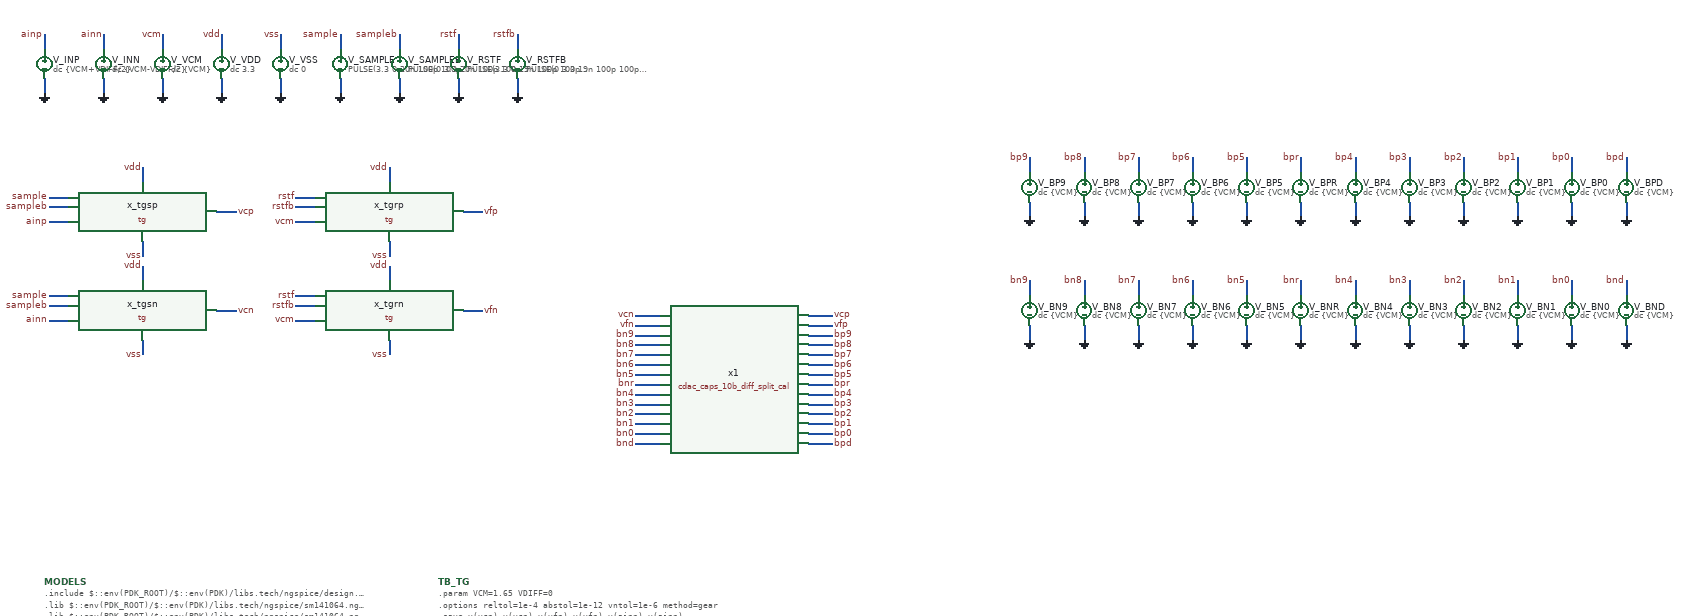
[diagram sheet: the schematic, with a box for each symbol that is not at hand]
v {xschem version=3.4.8RC file_version=1.3}
G {}
K {}
V {}
S {}
F {}
E {}
N 1650 -840 1700 -840 {
lab=vcp}
N 1650 -820 1700 -820 {
lab=vfp}
N 1650 -800 1700 -800 {
lab=bp9}
N 1650 -780 1700 -780 {
lab=bp8}
N 1650 -760 1700 -760 {
lab=bp7}
N 1650 -740 1700 -740 {
lab=bp6}
N 1650 -720 1700 -720 {
lab=bp5}
N 1650 -700 1700 -700 {
lab=bpr}
N 1650 -680 1700 -680 {
lab=bp4}
N 1650 -660 1700 -660 {
lab=bp3}
N 1650 -640 1700 -640 {
lab=bp2}
N 1650 -620 1700 -620 {
lab=bp1}
N 1650 -600 1700 -600 {
lab=bp0}
N 1650 -580 1700 -580 {
lab=bpd}
N 1300 -840 1350 -840 {
lab=vcn}
N 1300 -820 1350 -820 {
lab=vfn}
N 1300 -800 1350 -800 {
lab=bn9}
N 1300 -780 1350 -780 {
lab=bn8}
N 1300 -760 1350 -760 {
lab=bn7}
N 1300 -740 1350 -740 {
lab=bn6}
N 1300 -720 1350 -720 {
lab=bn5}
N 1300 -700 1350 -700 {
lab=bnr}
N 1300 -680 1350 -680 {
lab=bn4}
N 1300 -660 1350 -660 {
lab=bn3}
N 1300 -640 1350 -640 {
lab=bn2}
N 1300 -620 1350 -620 {
lab=bn1}
N 1300 -600 1350 -600 {
lab=bn0}
N 1300 -580 1350 -580 {
lab=bnd}
N 2100 -1160 2100 -1130 {
lab=bp9}
N 2100 -1070 2100 -1040 {
lab=GND}
N 2100 -910 2100 -880 {
lab=bn9}
N 2100 -820 2100 -790 {
lab=GND}
N 2210 -1160 2210 -1130 {
lab=bp8}
N 2210 -1070 2210 -1040 {
lab=GND}
N 2210 -910 2210 -880 {
lab=bn8}
N 2210 -820 2210 -790 {
lab=GND}
N 2320 -1160 2320 -1130 {
lab=bp7}
N 2320 -1070 2320 -1040 {
lab=GND}
N 2320 -910 2320 -880 {
lab=bn7}
N 2320 -820 2320 -790 {
lab=GND}
N 2430 -1160 2430 -1130 {
lab=bp6}
N 2430 -1070 2430 -1040 {
lab=GND}
N 2430 -910 2430 -880 {
lab=bn6}
N 2430 -820 2430 -790 {
lab=GND}
N 2540 -1160 2540 -1130 {
lab=bp5}
N 2540 -1070 2540 -1040 {
lab=GND}
N 2540 -910 2540 -880 {
lab=bn5}
N 2540 -820 2540 -790 {
lab=GND}
N 2650 -1160 2650 -1130 {
lab=bpr}
N 2650 -1070 2650 -1040 {
lab=GND}
N 2650 -910 2650 -880 {
lab=bnr}
N 2650 -820 2650 -790 {
lab=GND}
N 2760 -1160 2760 -1130 {
lab=bp4}
N 2760 -1070 2760 -1040 {
lab=GND}
N 2760 -910 2760 -880 {
lab=bn4}
N 2760 -820 2760 -790 {
lab=GND}
N 2870 -1160 2870 -1130 {
lab=bp3}
N 2870 -1070 2870 -1040 {
lab=GND}
N 2870 -910 2870 -880 {
lab=bn3}
N 2870 -820 2870 -790 {
lab=GND}
N 2980 -1160 2980 -1130 {
lab=bp2}
N 2980 -1070 2980 -1040 {
lab=GND}
N 2980 -910 2980 -880 {
lab=bn2}
N 2980 -820 2980 -790 {
lab=GND}
N 3090 -1160 3090 -1130 {
lab=bp1}
N 3090 -1070 3090 -1040 {
lab=GND}
N 3090 -910 3090 -880 {
lab=bn1}
N 3090 -820 3090 -790 {
lab=GND}
N 3200 -1160 3200 -1130 {
lab=bp0}
N 3200 -1070 3200 -1040 {
lab=GND}
N 3200 -910 3200 -880 {
lab=bn0}
N 3200 -820 3200 -790 {
lab=GND}
N 3310 -1160 3310 -1130 {
lab=bpd}
N 3310 -1070 3310 -1040 {
lab=GND}
N 3310 -910 3310 -880 {
lab=bnd}
N 3310 -820 3310 -790 {
lab=GND}
N 100 -1410 100 -1380 {
lab=ainp}
N 100 -1320 100 -1290 {
lab=GND}
N 220 -1410 220 -1380 {
lab=ainn}
N 220 -1320 220 -1290 {
lab=GND}
N 340 -1410 340 -1380 {
lab=vcm}
N 340 -1320 340 -1290 {
lab=GND}
N 460 -1410 460 -1380 {
lab=vdd}
N 460 -1320 460 -1290 {
lab=GND}
N 580 -1410 580 -1380 {
lab=vss}
N 580 -1320 580 -1290 {
lab=GND}
N 700 -1410 700 -1380 {
lab=sample}
N 700 -1320 700 -1290 {
lab=GND}
N 820 -1410 820 -1380 {
lab=sampleb}
N 820 -1320 820 -1290 {
lab=GND}
N 940 -1410 940 -1380 {
lab=rstf}
N 940 -1320 940 -1290 {
lab=GND}
N 1060 -1410 1060 -1380 {
lab=rstfb}
N 1060 -1320 1060 -1290 {
lab=GND}
N 110 -1080 150 -1080 {
lab=sample}
N 110 -1060 150 -1060 {
lab=sampleb}
N 110 -1030 150 -1030 {
lab=ainp}
N 450 -1050 490 -1050 {
lab=vcp}
N 300 -1140 300 -1110 {
lab=vdd}
N 300 -990 300 -960 {
lab=vss}
N 110 -880 150 -880 {
lab=sample}
N 110 -860 150 -860 {
lab=sampleb}
N 110 -830 150 -830 {
lab=ainn}
N 450 -850 490 -850 {
lab=vcn}
N 300 -940 300 -910 {
lab=vdd}
N 300 -790 300 -760 {
lab=vss}
N 610 -1080 650 -1080 {
lab=rstf}
N 610 -1060 650 -1060 {
lab=rstfb}
N 610 -1030 650 -1030 {
lab=vcm}
N 950 -1050 990 -1050 {
lab=vfp}
N 800 -1140 800 -1110 {
lab=vdd}
N 800 -990 800 -960 {
lab=vss}
N 610 -880 650 -880 {
lab=rstf}
N 610 -860 650 -860 {
lab=rstfb}
N 610 -830 650 -830 {
lab=vcm}
N 950 -850 990 -850 {
lab=vfn}
N 800 -940 800 -910 {
lab=vdd}
N 800 -790 800 -760 {
lab=vss}
C {cdac_caps_10b_diff_split_cal.sym} 1500 -700 0 0 {name=x1}
C {lab_pin.sym} 1700 -840 2 0 {name=l_vcp sig_type=std_logic lab=vcp}
C {lab_pin.sym} 1700 -820 2 0 {name=l_vfp sig_type=std_logic lab=vfp}
C {lab_pin.sym} 1700 -800 2 0 {name=l_bp9 sig_type=std_logic lab=bp9}
C {lab_pin.sym} 1700 -780 2 0 {name=l_bp8 sig_type=std_logic lab=bp8}
C {lab_pin.sym} 1700 -760 2 0 {name=l_bp7 sig_type=std_logic lab=bp7}
C {lab_pin.sym} 1700 -740 2 0 {name=l_bp6 sig_type=std_logic lab=bp6}
C {lab_pin.sym} 1700 -720 2 0 {name=l_bp5 sig_type=std_logic lab=bp5}
C {lab_pin.sym} 1700 -700 2 0 {name=l_bpr sig_type=std_logic lab=bpr}
C {lab_pin.sym} 1700 -680 2 0 {name=l_bp4 sig_type=std_logic lab=bp4}
C {lab_pin.sym} 1700 -660 2 0 {name=l_bp3 sig_type=std_logic lab=bp3}
C {lab_pin.sym} 1700 -640 2 0 {name=l_bp2 sig_type=std_logic lab=bp2}
C {lab_pin.sym} 1700 -620 2 0 {name=l_bp1 sig_type=std_logic lab=bp1}
C {lab_pin.sym} 1700 -600 2 0 {name=l_bp0 sig_type=std_logic lab=bp0}
C {lab_pin.sym} 1700 -580 2 0 {name=l_bpd sig_type=std_logic lab=bpd}
C {lab_pin.sym} 1300 -840 0 0 {name=l_vcn sig_type=std_logic lab=vcn}
C {lab_pin.sym} 1300 -820 0 0 {name=l_vfn sig_type=std_logic lab=vfn}
C {lab_pin.sym} 1300 -800 0 0 {name=l_bn9 sig_type=std_logic lab=bn9}
C {lab_pin.sym} 1300 -780 0 0 {name=l_bn8 sig_type=std_logic lab=bn8}
C {lab_pin.sym} 1300 -760 0 0 {name=l_bn7 sig_type=std_logic lab=bn7}
C {lab_pin.sym} 1300 -740 0 0 {name=l_bn6 sig_type=std_logic lab=bn6}
C {lab_pin.sym} 1300 -720 0 0 {name=l_bn5 sig_type=std_logic lab=bn5}
C {lab_pin.sym} 1300 -700 0 0 {name=l_bnr sig_type=std_logic lab=bnr}
C {lab_pin.sym} 1300 -680 0 0 {name=l_bn4 sig_type=std_logic lab=bn4}
C {lab_pin.sym} 1300 -660 0 0 {name=l_bn3 sig_type=std_logic lab=bn3}
C {lab_pin.sym} 1300 -640 0 0 {name=l_bn2 sig_type=std_logic lab=bn2}
C {lab_pin.sym} 1300 -620 0 0 {name=l_bn1 sig_type=std_logic lab=bn1}
C {lab_pin.sym} 1300 -600 0 0 {name=l_bn0 sig_type=std_logic lab=bn0}
C {lab_pin.sym} 1300 -580 0 0 {name=l_bnd sig_type=std_logic lab=bnd}
C {vsource.sym} 2100 -1100 0 0 {name=V_BP9 value="dc \{VCM\}" savecurrent=false}
C {lab_pin.sym} 2100 -1160 0 0 {name=lV_BP9 sig_type=std_logic lab=bp9}
C {gnd.sym} 2100 -1040 0 0 {name=gV_BP9 lab=GND}
C {vsource.sym} 2100 -850 0 0 {name=V_BN9 value="dc \{VCM\}" savecurrent=false}
C {lab_pin.sym} 2100 -910 0 0 {name=lV_BN9 sig_type=std_logic lab=bn9}
C {gnd.sym} 2100 -790 0 0 {name=gV_BN9 lab=GND}
C {vsource.sym} 2210 -1100 0 0 {name=V_BP8 value="dc \{VCM\}" savecurrent=false}
C {lab_pin.sym} 2210 -1160 0 0 {name=lV_BP8 sig_type=std_logic lab=bp8}
C {gnd.sym} 2210 -1040 0 0 {name=gV_BP8 lab=GND}
C {vsource.sym} 2210 -850 0 0 {name=V_BN8 value="dc \{VCM\}" savecurrent=false}
C {lab_pin.sym} 2210 -910 0 0 {name=lV_BN8 sig_type=std_logic lab=bn8}
C {gnd.sym} 2210 -790 0 0 {name=gV_BN8 lab=GND}
C {vsource.sym} 2320 -1100 0 0 {name=V_BP7 value="dc \{VCM\}" savecurrent=false}
C {lab_pin.sym} 2320 -1160 0 0 {name=lV_BP7 sig_type=std_logic lab=bp7}
C {gnd.sym} 2320 -1040 0 0 {name=gV_BP7 lab=GND}
C {vsource.sym} 2320 -850 0 0 {name=V_BN7 value="dc \{VCM\}" savecurrent=false}
C {lab_pin.sym} 2320 -910 0 0 {name=lV_BN7 sig_type=std_logic lab=bn7}
C {gnd.sym} 2320 -790 0 0 {name=gV_BN7 lab=GND}
C {vsource.sym} 2430 -1100 0 0 {name=V_BP6 value="dc \{VCM\}" savecurrent=false}
C {lab_pin.sym} 2430 -1160 0 0 {name=lV_BP6 sig_type=std_logic lab=bp6}
C {gnd.sym} 2430 -1040 0 0 {name=gV_BP6 lab=GND}
C {vsource.sym} 2430 -850 0 0 {name=V_BN6 value="dc \{VCM\}" savecurrent=false}
C {lab_pin.sym} 2430 -910 0 0 {name=lV_BN6 sig_type=std_logic lab=bn6}
C {gnd.sym} 2430 -790 0 0 {name=gV_BN6 lab=GND}
C {vsource.sym} 2540 -1100 0 0 {name=V_BP5 value="dc \{VCM\}" savecurrent=false}
C {lab_pin.sym} 2540 -1160 0 0 {name=lV_BP5 sig_type=std_logic lab=bp5}
C {gnd.sym} 2540 -1040 0 0 {name=gV_BP5 lab=GND}
C {vsource.sym} 2540 -850 0 0 {name=V_BN5 value="dc \{VCM\}" savecurrent=false}
C {lab_pin.sym} 2540 -910 0 0 {name=lV_BN5 sig_type=std_logic lab=bn5}
C {gnd.sym} 2540 -790 0 0 {name=gV_BN5 lab=GND}
C {vsource.sym} 2650 -1100 0 0 {name=V_BPR value="dc \{VCM\}" savecurrent=false}
C {lab_pin.sym} 2650 -1160 0 0 {name=lV_BPR sig_type=std_logic lab=bpr}
C {gnd.sym} 2650 -1040 0 0 {name=gV_BPR lab=GND}
C {vsource.sym} 2650 -850 0 0 {name=V_BNR value="dc \{VCM\}" savecurrent=false}
C {lab_pin.sym} 2650 -910 0 0 {name=lV_BNR sig_type=std_logic lab=bnr}
C {gnd.sym} 2650 -790 0 0 {name=gV_BNR lab=GND}
C {vsource.sym} 2760 -1100 0 0 {name=V_BP4 value="dc \{VCM\}" savecurrent=false}
C {lab_pin.sym} 2760 -1160 0 0 {name=lV_BP4 sig_type=std_logic lab=bp4}
C {gnd.sym} 2760 -1040 0 0 {name=gV_BP4 lab=GND}
C {vsource.sym} 2760 -850 0 0 {name=V_BN4 value="dc \{VCM\}" savecurrent=false}
C {lab_pin.sym} 2760 -910 0 0 {name=lV_BN4 sig_type=std_logic lab=bn4}
C {gnd.sym} 2760 -790 0 0 {name=gV_BN4 lab=GND}
C {vsource.sym} 2870 -1100 0 0 {name=V_BP3 value="dc \{VCM\}" savecurrent=false}
C {lab_pin.sym} 2870 -1160 0 0 {name=lV_BP3 sig_type=std_logic lab=bp3}
C {gnd.sym} 2870 -1040 0 0 {name=gV_BP3 lab=GND}
C {vsource.sym} 2870 -850 0 0 {name=V_BN3 value="dc \{VCM\}" savecurrent=false}
C {lab_pin.sym} 2870 -910 0 0 {name=lV_BN3 sig_type=std_logic lab=bn3}
C {gnd.sym} 2870 -790 0 0 {name=gV_BN3 lab=GND}
C {vsource.sym} 2980 -1100 0 0 {name=V_BP2 value="dc \{VCM\}" savecurrent=false}
C {lab_pin.sym} 2980 -1160 0 0 {name=lV_BP2 sig_type=std_logic lab=bp2}
C {gnd.sym} 2980 -1040 0 0 {name=gV_BP2 lab=GND}
C {vsource.sym} 2980 -850 0 0 {name=V_BN2 value="dc \{VCM\}" savecurrent=false}
C {lab_pin.sym} 2980 -910 0 0 {name=lV_BN2 sig_type=std_logic lab=bn2}
C {gnd.sym} 2980 -790 0 0 {name=gV_BN2 lab=GND}
C {vsource.sym} 3090 -1100 0 0 {name=V_BP1 value="dc \{VCM\}" savecurrent=false}
C {lab_pin.sym} 3090 -1160 0 0 {name=lV_BP1 sig_type=std_logic lab=bp1}
C {gnd.sym} 3090 -1040 0 0 {name=gV_BP1 lab=GND}
C {vsource.sym} 3090 -850 0 0 {name=V_BN1 value="dc \{VCM\}" savecurrent=false}
C {lab_pin.sym} 3090 -910 0 0 {name=lV_BN1 sig_type=std_logic lab=bn1}
C {gnd.sym} 3090 -790 0 0 {name=gV_BN1 lab=GND}
C {vsource.sym} 3200 -1100 0 0 {name=V_BP0 value="dc \{VCM\}" savecurrent=false}
C {lab_pin.sym} 3200 -1160 0 0 {name=lV_BP0 sig_type=std_logic lab=bp0}
C {gnd.sym} 3200 -1040 0 0 {name=gV_BP0 lab=GND}
C {vsource.sym} 3200 -850 0 0 {name=V_BN0 value="dc \{VCM\}" savecurrent=false}
C {lab_pin.sym} 3200 -910 0 0 {name=lV_BN0 sig_type=std_logic lab=bn0}
C {gnd.sym} 3200 -790 0 0 {name=gV_BN0 lab=GND}
C {vsource.sym} 3310 -1100 0 0 {name=V_BPD value="dc \{VCM\}" savecurrent=false}
C {lab_pin.sym} 3310 -1160 0 0 {name=lV_BPD sig_type=std_logic lab=bpd}
C {gnd.sym} 3310 -1040 0 0 {name=gV_BPD lab=GND}
C {vsource.sym} 3310 -850 0 0 {name=V_BND value="dc \{VCM\}" savecurrent=false}
C {lab_pin.sym} 3310 -910 0 0 {name=lV_BND sig_type=std_logic lab=bnd}
C {gnd.sym} 3310 -790 0 0 {name=gV_BND lab=GND}
C {vsource.sym} 100 -1350 0 0 {name=V_INP value="dc \{VCM+VDIFF/2\}" savecurrent=false}
C {lab_pin.sym} 100 -1410 0 0 {name=lV_INP sig_type=std_logic lab=ainp}
C {gnd.sym} 100 -1290 0 0 {name=gV_INP lab=GND}
C {vsource.sym} 220 -1350 0 0 {name=V_INN value="dc \{VCM-VDIFF/2\}" savecurrent=false}
C {lab_pin.sym} 220 -1410 0 0 {name=lV_INN sig_type=std_logic lab=ainn}
C {gnd.sym} 220 -1290 0 0 {name=gV_INN lab=GND}
C {vsource.sym} 340 -1350 0 0 {name=V_VCM value="dc \{VCM\}" savecurrent=false}
C {lab_pin.sym} 340 -1410 0 0 {name=lV_VCM sig_type=std_logic lab=vcm}
C {gnd.sym} 340 -1290 0 0 {name=gV_VCM lab=GND}
C {vsource.sym} 460 -1350 0 0 {name=V_VDD value="dc 3.3" savecurrent=false}
C {lab_pin.sym} 460 -1410 0 0 {name=lV_VDD sig_type=std_logic lab=vdd}
C {gnd.sym} 460 -1290 0 0 {name=gV_VDD lab=GND}
C {vsource.sym} 580 -1350 0 0 {name=V_VSS value="dc 0" savecurrent=false}
C {lab_pin.sym} 580 -1410 0 0 {name=lV_VSS sig_type=std_logic lab=vss}
C {gnd.sym} 580 -1290 0 0 {name=gV_VSS lab=GND}
C {vsource.sym} 700 -1350 0 0 {name=V_SAMPLE value="PULSE(3.3 0 20n 100p 100p 1 2)" savecurrent=false}
C {lab_pin.sym} 700 -1410 0 0 {name=lV_SAMPLE sig_type=std_logic lab=sample}
C {gnd.sym} 700 -1290 0 0 {name=gV_SAMPLE lab=GND}
C {vsource.sym} 820 -1350 0 0 {name=V_SAMPLEB value="PULSE(0 3.3 20n 100p 100p 1 2)" savecurrent=false}
C {lab_pin.sym} 820 -1410 0 0 {name=lV_SAMPLEB sig_type=std_logic lab=sampleb}
C {gnd.sym} 820 -1290 0 0 {name=gV_SAMPLEB lab=GND}
C {vsource.sym} 940 -1350 0 0 {name=V_RSTF value="PULSE(3.3 0 19n 100p 100p 1 2)" savecurrent=false}
C {lab_pin.sym} 940 -1410 0 0 {name=lV_RSTF sig_type=std_logic lab=rstf}
C {gnd.sym} 940 -1290 0 0 {name=gV_RSTF lab=GND}
C {vsource.sym} 1060 -1350 0 0 {name=V_RSTFB value="PULSE(0 3.3 19n 100p 100p 1 2)" savecurrent=false}
C {lab_pin.sym} 1060 -1410 0 0 {name=lV_RSTFB sig_type=std_logic lab=rstfb}
C {gnd.sym} 1060 -1290 0 0 {name=gV_RSTFB lab=GND}
C {tg.sym} 300 -1050 0 0 {name=x_tgsp}
C {lab_pin.sym} 110 -1080 0 0 {name=lx_tgspsample sig_type=std_logic lab=sample}
C {lab_pin.sym} 110 -1060 0 0 {name=lx_tgspsampleb sig_type=std_logic lab=sampleb}
C {lab_pin.sym} 110 -1030 0 0 {name=lx_tgspainp sig_type=std_logic lab=ainp}
C {lab_pin.sym} 490 -1050 2 0 {name=lx_tgspvcp sig_type=std_logic lab=vcp}
C {lab_pin.sym} 300 -1140 0 0 {name=lx_tgspvdd sig_type=std_logic lab=vdd}
C {lab_pin.sym} 300 -960 0 0 {name=lx_tgspvss sig_type=std_logic lab=vss}
C {tg.sym} 300 -850 0 0 {name=x_tgsn}
C {lab_pin.sym} 110 -880 0 0 {name=lx_tgsnsample sig_type=std_logic lab=sample}
C {lab_pin.sym} 110 -860 0 0 {name=lx_tgsnsampleb sig_type=std_logic lab=sampleb}
C {lab_pin.sym} 110 -830 0 0 {name=lx_tgsnainn sig_type=std_logic lab=ainn}
C {lab_pin.sym} 490 -850 2 0 {name=lx_tgsnvcn sig_type=std_logic lab=vcn}
C {lab_pin.sym} 300 -940 0 0 {name=lx_tgsnvdd sig_type=std_logic lab=vdd}
C {lab_pin.sym} 300 -760 0 0 {name=lx_tgsnvss sig_type=std_logic lab=vss}
C {tg.sym} 800 -1050 0 0 {name=x_tgrp}
C {lab_pin.sym} 610 -1080 0 0 {name=lx_tgrprstf sig_type=std_logic lab=rstf}
C {lab_pin.sym} 610 -1060 0 0 {name=lx_tgrprstfb sig_type=std_logic lab=rstfb}
C {lab_pin.sym} 610 -1030 0 0 {name=lx_tgrpvcm sig_type=std_logic lab=vcm}
C {lab_pin.sym} 990 -1050 2 0 {name=lx_tgrpvfp sig_type=std_logic lab=vfp}
C {lab_pin.sym} 800 -1140 0 0 {name=lx_tgrpvdd sig_type=std_logic lab=vdd}
C {lab_pin.sym} 800 -960 0 0 {name=lx_tgrpvss sig_type=std_logic lab=vss}
C {tg.sym} 800 -850 0 0 {name=x_tgrn}
C {lab_pin.sym} 610 -880 0 0 {name=lx_tgrnrstf sig_type=std_logic lab=rstf}
C {lab_pin.sym} 610 -860 0 0 {name=lx_tgrnrstfb sig_type=std_logic lab=rstfb}
C {lab_pin.sym} 610 -830 0 0 {name=lx_tgrnvcm sig_type=std_logic lab=vcm}
C {lab_pin.sym} 990 -850 2 0 {name=lx_tgrnvfn sig_type=std_logic lab=vfn}
C {lab_pin.sym} 800 -940 0 0 {name=lx_tgrnvdd sig_type=std_logic lab=vdd}
C {lab_pin.sym} 800 -760 0 0 {name=lx_tgrnvss sig_type=std_logic lab=vss}
C {code_shown.sym} 100 -300 0 0 {name=MODELS only_toplevel=true
format="tcleval( @value )"
value="
.include $::env(PDK_ROOT)/$::env(PDK)/libs.tech/ngspice/design.ngspice
.lib $::env(PDK_ROOT)/$::env(PDK)/libs.tech/ngspice/sm141064.ngspice typical
.lib $::env(PDK_ROOT)/$::env(PDK)/libs.tech/ngspice/sm141064.ngspice cap_mim
.lib $::env(PDK_ROOT)/$::env(PDK)/libs.tech/ngspice/sm141064.ngspice mimcap_typical
"}
C {code.sym} 900 -300 0 0 {name=TB_TG only_toplevel=true
value="
.param VCM=1.65 VDIFF=0
.options reltol=1e-4 abstol=1e-12 vntol=1e-6 method=gear
.save v(vcp) v(vcn) v(vfp) v(vfn) v(ainp) v(ainn)

.control
set noaskquit
shell rm -f split_cal_tg.txt
foreach vd -1.5 -0.75 -0.2 0.0 0.2 0.75 1.5
  alterparam VDIFF=$vd
  reset
  tran 20p 1.03u
  meas tran p18 find v(vcp) at=18n
  meas tran n18 find v(vcn) at=18n
  meas tran p25 find v(vcp) at=25n
  meas tran n25 find v(vcn) at=25n
  meas tran fp25 find v(vfp) at=25n
  meas tran fn25 find v(vfn) at=25n
  meas tran p1u find v(vcp) at=1.025u
  meas tran n1u find v(vcn) at=1.025u
  let trk = (p18-n18) - $vd
  let err = (p25-n25) - $vd
  let cm = (p25+n25)/2 - 1.65
  let drift = (p1u-n1u) - (p25-n25)
  echo TG $vd $&trk $&err $&cm $&fp25 $&fn25 $&drift >> split_cal_tg.txt
  destroy all
end
* reversed order (NOT the proposed sequence): fine reset released 1 ns AFTER the sampler
foreach vd -1.5 -0.75 -0.2 0.0 0.2 0.75 1.5
  alterparam VDIFF=$vd
  reset
  alter @v_rstf[pulse] = [ 3.3 0 21n 100p 100p 1 2 ]
  alter @v_rstfb[pulse] = [ 0 3.3 21n 100p 100p 1 2 ]
  tran 20p 1.03u
  meas tran p18 find v(vcp) at=18n
  meas tran n18 find v(vcn) at=18n
  meas tran p25 find v(vcp) at=25n
  meas tran n25 find v(vcn) at=25n
  meas tran fp25 find v(vfp) at=25n
  meas tran fn25 find v(vfn) at=25n
  meas tran p1u find v(vcp) at=1.025u
  meas tran n1u find v(vcn) at=1.025u
  let trk = (p18-n18) - $vd
  let err = (p25-n25) - $vd
  let cm = (p25+n25)/2 - 1.65
  let drift = (p1u-n1u) - (p25-n25)
  echo TGREV $vd $&trk $&err $&cm $&fp25 $&fn25 $&drift >> split_cal_tg.txt
  destroy all
end
echo done
.endc
"}
C {title.sym} 160 0 0 0 {name=l1 author="Arjun Ananth"}
